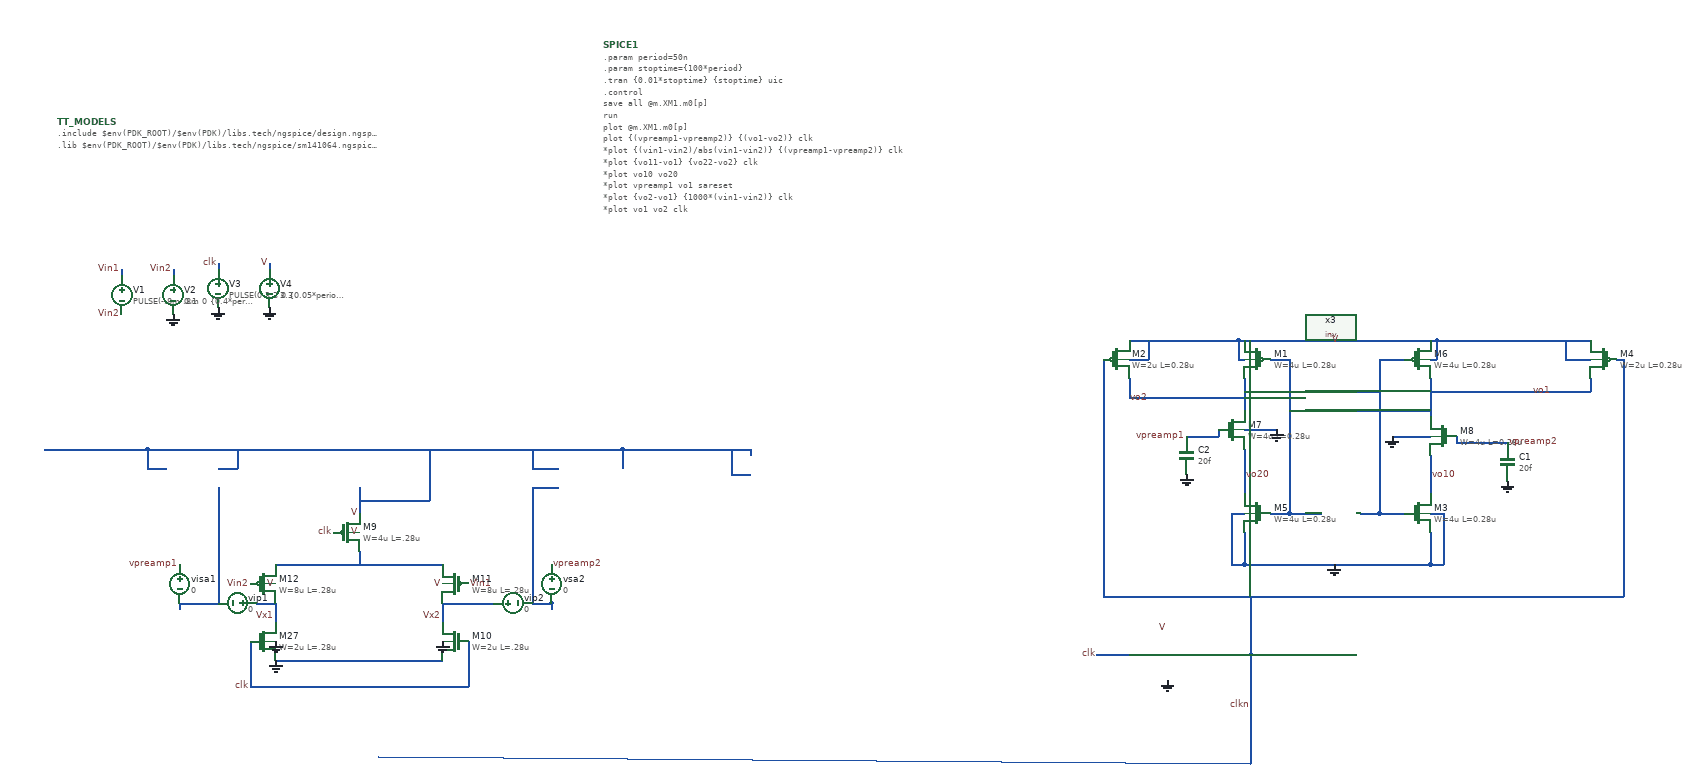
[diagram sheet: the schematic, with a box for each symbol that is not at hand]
v {xschem version=3.4.6RC file_version=1.2
}
G {}
K {}
V {}
S {}
E {}
N 260 -220 260 -210 {
lab=V}
N 180 -220 180 -210 {
lab=clk}
N 1780 200 1780 250 {
lab=GND}
N 1840 300 2340 300 {
lab=clkn}
N 2070 200 2070 250 {
lab=GND}
N 1760 170 1780 170 {
lab=GND}
N 1760 170 1760 250 {
lab=GND}
N 2070 170 2090 170 {
lab=GND}
N 2090 170 2090 250 {
lab=GND}
N 2070 130 2070 140 {
lab=vo10}
N 2070 -40 2070 20 {
lab=vo1}
N 2010 -100 2080 -100 {
lab=V}
N 1780 130 1780 140 {
lab=vo20}
N 1780 -40 1780 10 {
lab=vo2}
N 1770 -70 1780 -70 {
lab=V}
N 1770 -100 1770 -70 {
lab=V}
N 2070 -70 2080 -70 {
lab=V}
N 2080 -100 2080 -70 {
lab=V}
N 1820 -70 1850 -70 {
lab=vo1}
N 1820 170 1850 170 {
lab=vo1}
N 1850 90 1850 170 {
lab=vo1}
N 1780 40 1830 40 {
lab=GND}
N 1990 130 1990 170 {
lab=vo2}
N 1990 170 2030 170 {
lab=vo2}
N 2010 50 2070 50 {
lab=GND}
N 1990 -70 2030 -70 {
lab=vo2}
N 1760 250 1780 250 {
lab=GND}
N 1910 250 2070 250 {
lab=GND}
N 2070 250 2090 250 {
lab=GND}
N 1770 -100 1830 -100 {
lab=V}
N 1930 -100 2010 -100 {
lab=V}
N 1850 -70 1850 90 {
lab=vo1}
N 2070 80 2070 90 {
lab=vo10}
N 1780 70 1780 130 {
lab=vo20}
N 1990 -70 1990 130 {
lab=vo2}
N 2070 90 2070 130 {
lab=vo10}
N 1830 -100 1930 -100 {
lab=V}
N 1780 250 1910 250 {
lab=GND}
N 1550 390 1600 390 {
lab=clk}
N 110 -210 110 -200 {
lab=Vin2}
N 30 -210 30 -200 {
lab=Vin1}
N 700 310 700 320 {lab=#net1}
N 2080 -100 2320 -100 {lab=V}
N 1600 -100 1770 -100 {lab=V}
N 1600 -70 1630 -70 {lab=V}
N 1630 -100 1630 -70 {lab=V}
N 2280 -70 2320 -70 {lab=V}
N 2280 -100 2280 -70 {lab=V}
N 1600 -40 1600 -10 {lab=vo2}
N 1600 -10 1780 -10 {lab=vo2}
N 2070 -20 2320 -20 {lab=vo1}
N 2320 -40 2320 -20 {lab=vo1}
N 2340 300 2370 300 {lab=clkn}
N 2370 -70 2370 300 {lab=clkn}
N 2360 -70 2370 -70 {lab=clkn}
N 1560 -70 1560 250 {lab=clkn}
N 1560 250 1560 300 {lab=clkn}
N 1560 300 1840 300 {lab=clkn}
N 270 250 530 250 {lab=#net2}
N 400 230 400 250 {lab=#net2}
N 270 400 530 400 {lab=GND}
N 230 370 230 440 {lab=clk}
N 230 440 570 440 {lab=clk}
N 570 370 570 440 {lab=clk}
N 700 310 700 320 {lab=#net1}
N 120 310 120 320 {lab=#net3}
N 120 310 180 310 {lab=#net3}
N 240 310 270 310 {lab=Vx1}
N 530 310 610 310 {lab=Vx2}
N 670 310 700 310 {lab=#net1}
N 1780 -20 1990 -20 {lab=vo2}
N 1850 10 2070 10 {lab=vo1}
N 530 310 530 340 {lab=Vx2}
N 270 310 270 340 {lab=Vx1}
N 100 70 790 70 {lab=V}
N 70 100 100 100 {lab=V}
N 70 70 70 100 {lab=V}
N 70 70 100 70 {lab=V}
N 180 100 210 100 {lab=V}
N 210 70 210 100 {lab=V}
N 670 100 710 100 {lab=V}
N 670 70 670 100 {lab=V}
N 810 70 810 100 {lab=V}
N 790 70 810 70 {lab=V}
N 180 130 180 310 {lab=#net3}
N 670 130 710 130 {lab=#net1}
N 670 130 670 310 {lab=#net1}
N 1790 390 1790 560 {lab=clkn}
N 430 550 1790 560 {lab=clkn}
N 1760 390 1790 390 {lab=clkn}
N 1790 300 1790 390 {lab=clkn}
N 980 110 1010 110 {lab=V}
N 980 80 980 110 {lab=V}
N -90 70 70 70 {lab=V}
N 810 70 1010 70 {lab=V}
N 1010 70 1010 80 {lab=V}
N 980 70 980 80 {lab=V}
N 1740 40 1740 50 {lab=vpreamp1}
N 1690 50 1740 50 {lab=vpreamp1}
N 2110 60 2190 60 {lab=vpreamp2}
N 2110 50 2110 60 {lab=vpreamp2}
N 1850 170 1900 170 {lab=vo1}
N 1960 170 1990 170 {lab=vo2}
N 400 130 400 170 {lab=V}
N 400 150 510 150 {lab=V}
N 510 70 510 150 {lab=V}
C {devices/vsource.sym} 180 -180 0 0 {name=V3 value="PULSE(0 3.3 0 \{0.05*period\} \{0.05*period\} \{0.5*period\} \{1*period\})"}
C {devices/gnd.sym} 180 -150 0 0 {name=l4 lab=GND}
C {devices/lab_wire.sym} 180 -220 0 0 {name=p3 sig_type=std_logic lab=clk
}
C {devices/vsource.sym} 260 -180 0 0 {name=V4 value=3.3}
C {devices/gnd.sym} 260 -150 0 0 {name=l5 lab=GND}
C {devices/lab_wire.sym} 260 -220 0 0 {name=p7 sig_type=std_logic lab=V
}
C {devices/code_shown.sym} 780 -560 0 0 {name=SPICE1 only_toplevel=false value="

.param period=50n
.param stoptime=\{100*period\}
.tran \{0.01*stoptime\} \{stoptime\} uic 
.control
save all @m.XM1.m0[p] 
run
plot @m.XM1.m0[p]
plot \{(vpreamp1-vpreamp2)\} \{(vo1-vo2)\} clk
*plot \{(vin1-vin2)/abs(vin1-vin2)\} \{(vpreamp1-vpreamp2)\} clk
*plot \{vo11-vo1\} \{vo22-vo2\} clk
*plot vo10 vo20
*plot vpreamp1 vo1 sareset
*plot \{vo2-vo1\} \{1000*(vin1-vin2)\} clk
*plot vo1 vo2 clk
*plot \{(vin1-vin2)*10\} \{(vpreamp1-vpreamp2)\} \{clk /330\} \{vin2/(100)\}
*plot \{(vin1-vin2)*1000\} vpreamp1 vpreamp2 \{clk\} \{vin2\}
plot \{(vpreamp1-vpreamp2)\} \{(vin1-vin2)\} \{clk / 3300\}
*plot X Y clk
*plot \{(X-Y)\} \{clk/3000\}
*plot clk sareset
*plot i(vip1) i(vip2) i(visa1) i(vsa2) clk/3300
plot  \{vo1-vo2\} clk
plot \{vx1-vx2\} \{clk/30\}
plot \{vo10-vo20\} clk
.endc"}
C {devices/code.sym} -70 -440 0 0 {name=TT_MODELS 
only_toplevel=true 
format="tcleval(  @value  )"
value="
.include $env(PDK_ROOT)/$env(PDK)/libs.tech/ngspice/design.ngspice
.lib $env(PDK_ROOT)/$env(PDK)/libs.tech/ngspice/sm141064.ngspice typical
"
spice_ignore=false}
C {symbols/pfet_03v3.sym} 1800 -70 0 1 {name=M1
L=0.28u
W=4u
nf=1
m=1
ad="'int((nf+1)/2) * W/nf * 0.18u'"
pd="'2*int((nf+1)/2) * (W/nf + 0.18u)'"
as="'int((nf+2)/2) * W/nf * 0.18u'"
ps="'2*int((nf+2)/2) * (W/nf + 0.18u)'"
nrd="'0.18u / W'" nrs="'0.18u / W'"
sa=0 sb=0 sd=0
model=pfet_03v3
spiceprefix=X
}
C {symbols/pfet_03v3.sym} 1580 -70 0 0 {name=M2
L=0.28u
W=2u
nf=1
m=1
ad="'int((nf+1)/2) * W/nf * 0.18u'"
pd="'2*int((nf+1)/2) * (W/nf + 0.18u)'"
as="'int((nf+2)/2) * W/nf * 0.18u'"
ps="'2*int((nf+2)/2) * (W/nf + 0.18u)'"
nrd="'0.18u / W'" nrs="'0.18u / W'"
sa=0 sb=0 sd=0
model=pfet_03v3
spiceprefix=X
}
C {symbols/nfet_03v3.sym} 2050 170 0 0 {name=M3
L=0.28u
W=4u
nf=1
m=1
ad="'int((nf+1)/2) * W/nf * 0.18u'"
pd="'2*int((nf+1)/2) * (W/nf + 0.18u)'"
as="'int((nf+2)/2) * W/nf * 0.18u'"
ps="'2*int((nf+2)/2) * (W/nf + 0.18u)'"
nrd="'0.18u / W'" nrs="'0.18u / W'"
sa=0 sb=0 sd=0
model=nfet_03v3
spiceprefix=X
}
C {symbols/pfet_03v3.sym} 2340 -70 0 1 {name=M4
L=0.28u
W=2u
nf=1
m=1
ad="'int((nf+1)/2) * W/nf * 0.18u'"
pd="'2*int((nf+1)/2) * (W/nf + 0.18u)'"
as="'int((nf+2)/2) * W/nf * 0.18u'"
ps="'2*int((nf+2)/2) * (W/nf + 0.18u)'"
nrd="'0.18u / W'" nrs="'0.18u / W'"
sa=0 sb=0 sd=0
model=pfet_03v3
spiceprefix=X
}
C {symbols/nfet_03v3.sym} 1800 170 0 1 {name=M5
L=0.28u
W=4u
nf=1
m=1
ad="'int((nf+1)/2) * W/nf * 0.18u'"
pd="'2*int((nf+1)/2) * (W/nf + 0.18u)'"
as="'int((nf+2)/2) * W/nf * 0.18u'"
ps="'2*int((nf+2)/2) * (W/nf + 0.18u)'"
nrd="'0.18u / W'" nrs="'0.18u / W'"
sa=0 sb=0 sd=0
model=nfet_03v3
spiceprefix=X
}
C {symbols/pfet_03v3.sym} 2050 -70 0 0 {name=M6
L=0.28u
W=4u
nf=1
m=1
ad="'int((nf+1)/2) * W/nf * 0.18u'"
pd="'2*int((nf+1)/2) * (W/nf + 0.18u)'"
as="'int((nf+2)/2) * W/nf * 0.18u'"
ps="'2*int((nf+2)/2) * (W/nf + 0.18u)'"
nrd="'0.18u / W'" nrs="'0.18u / W'"
sa=0 sb=0 sd=0
model=pfet_03v3
spiceprefix=X
}
C {symbols/nfet_03v3.sym} 1760 40 0 0 {name=M7
L=0.28u
W=4u
nf=1
m=1
ad="'int((nf+1)/2) * W/nf * 0.18u'"
pd="'2*int((nf+1)/2) * (W/nf + 0.18u)'"
as="'int((nf+2)/2) * W/nf * 0.18u'"
ps="'2*int((nf+2)/2) * (W/nf + 0.18u)'"
nrd="'0.18u / W'" nrs="'0.18u / W'"
sa=0 sb=0 sd=0
model=nfet_03v3
spiceprefix=X
}
C {symbols/nfet_03v3.sym} 2090 50 0 1 {name=M8
L=0.28u
W=4u
nf=1
m=1
ad="'int((nf+1)/2) * W/nf * 0.18u'"
pd="'2*int((nf+1)/2) * (W/nf + 0.18u)'"
as="'int((nf+2)/2) * W/nf * 0.18u'"
ps="'2*int((nf+2)/2) * (W/nf + 0.18u)'"
nrd="'0.18u / W'" nrs="'0.18u / W'"
sa=0 sb=0 sd=0
model=nfet_03v3
spiceprefix=X
}
C {inv.sym} 1660 390 0 0 {name=x3 cl=0.28u wp=0.44u wn=0.22u wx=5u}
C {symbols/nfet_03v3.sym} 250 370 0 0 {name=M27
L=.28u
W=2u
nf=1
m=1
ad="'int((nf+1)/2) * W/nf * 0.18u'"
pd="'2*int((nf+1)/2) * (W/nf + 0.18u)'"
as="'int((nf+2)/2) * W/nf * 0.18u'"
ps="'2*int((nf+2)/2) * (W/nf + 0.18u)'"
nrd="'0.18u / W'" nrs="'0.18u / W'"
sa=0 sb=0 sd=0
model=nfet_03v3
spiceprefix=X
}
C {devices/lab_wire.sym} 400 170 0 0 {name=p21 lab=V
W=3u}
C {symbols/pfet_03v3.sym} 380 200 2 1 {name=M9
L=.28u
W=4u
nf=1
m=1
ad="'int((nf+1)/2) * W/nf * 0.18u'"
pd="'2*int((nf+1)/2) * (W/nf + 0.18u)'"
as="'int((nf+2)/2) * W/nf * 0.18u'"
ps="'2*int((nf+2)/2) * (W/nf + 0.18u)'"
nrd="'0.18u / W'" nrs="'0.18u / W'"
sa=0 sb=0 sd=0
model=pfet_03v3
spiceprefix=X
}
C {symbols/pfet_03v3.sym} 550 280 0 1 {name=M11
L=.28u
W=8u
nf=1
m=1
ad="'int((nf+1)/2) * W/nf * 0.18u'"
pd="'2*int((nf+1)/2) * (W/nf + 0.18u)'"
as="'int((nf+2)/2) * W/nf * 0.18u'"
ps="'2*int((nf+2)/2) * (W/nf + 0.18u)'"
nrd="'0.18u / W'" nrs="'0.18u / W'"
sa=0 sb=0 sd=0
model=pfet_03v3
spiceprefix=X
}
C {symbols/pfet_03v3.sym} 250 280 0 0 {name=M12
L=.28u
W=8u
nf=1
m=1
ad="'int((nf+1)/2) * W/nf * 0.18u'"
pd="'2*int((nf+1)/2) * (W/nf + 0.18u)'"
as="'int((nf+2)/2) * W/nf * 0.18u'"
ps="'2*int((nf+2)/2) * (W/nf + 0.18u)'"
nrd="'0.18u / W'" nrs="'0.18u / W'"
sa=0 sb=0 sd=0
model=pfet_03v3
spiceprefix=X
}
C {devices/lab_wire.sym} 1930 -100 0 0 {name=p4 lab=V
W=3u}
C {devices/gnd.sym} 1660 430 0 0 {name=l1 lab=GND}
C {devices/gnd.sym} 270 400 0 0 {name=l2 lab=GND}
C {devices/lab_wire.sym} 230 280 0 0 {name=p5 sig_type=std_logic lab=Vin2}
C {devices/lab_wire.sym} 570 280 0 1 {name=p6 sig_type=std_logic lab=Vin1}
C {devices/lab_wire.sym} 230 440 0 0 {name=p8 sig_type=std_logic lab=clk
}
C {devices/lab_wire.sym} 1550 390 0 0 {name=p9 sig_type=std_logic lab=clk
}
C {devices/lab_wire.sym} 120 250 0 0 {name=p10 sig_type=std_logic lab=vpreamp1}
C {devices/lab_wire.sym} 1690 50 0 0 {name=p12 sig_type=std_logic lab=vpreamp1}
C {devices/lab_wire.sym} 2190 60 0 1 {name=p14 sig_type=std_logic lab=vpreamp2
}
C {devices/lab_wire.sym} 1660 350 0 0 {name=p16 lab=V
W=3u}
C {devices/lab_wire.sym} 2260 -20 0 0 {name=p15 sig_type=std_logic lab=vo1
}
C {devices/lab_wire.sym} 1600 -10 0 1 {name=p17 sig_type=std_logic lab=vo2}
C {devices/vsource.sym} 30 -170 0 0 {name=V1 value="PULSE(-.8m .8m 0 \{0.4*period\} \{0.4*period\} \{8*period\} \{16*period\})"}
C {devices/vsource.sym} 110 -170 0 0 {name=V2 value=0.1}
C {devices/gnd.sym} 110 -140 0 0 {name=l3 lab=GND}
C {devices/lab_wire.sym} 30 -210 0 0 {name=p1 sig_type=std_logic lab=Vin1}
C {devices/lab_wire.sym} 110 -210 0 0 {name=p2 sig_type=std_logic lab=Vin2}
C {devices/lab_wire.sym} 30 -140 0 0 {name=p13 sig_type=std_logic lab=Vin2}
C {devices/vsource.sym} 210 310 1 0 {name=vip1 value=0}
C {devices/vsource.sym} 120 280 0 0 {name=visa1 value=0}
C {devices/vsource.sym} 640 310 3 0 {name=vip2 value=0}
C {devices/vsource.sym} 700 280 0 0 {name=vsa2 value=0}
C {devices/lab_wire.sym} 700 250 0 1 {name=p23 sig_type=std_logic lab=vpreamp2
}
C {devices/gnd.sym} 1920 250 0 0 {name=l6 lab=GND}
C {symbols/nfet_03v3.sym} 550 370 0 1 {name=M10
L=.28u
W=2u
nf=1
m=1
ad="'int((nf+1)/2) * W/nf * 0.18u'"
pd="'2*int((nf+1)/2) * (W/nf + 0.18u)'"
as="'int((nf+2)/2) * W/nf * 0.18u'"
ps="'2*int((nf+2)/2) * (W/nf + 0.18u)'"
nrd="'0.18u / W'" nrs="'0.18u / W'"
sa=0 sb=0 sd=0
model=nfet_03v3
spiceprefix=X
}
C {devices/lab_wire.sym} 360 200 0 0 {name=p11 sig_type=std_logic lab=clk
}
C {devices/gnd.sym} 2010 50 0 0 {name=l9 lab=GND}
C {devices/gnd.sym} 1830 40 0 0 {name=l10 lab=GND}
C {devices/lab_wire.sym} 1780 110 0 1 {name=p19 sig_type=std_logic lab=vo20}
C {devices/lab_wire.sym} 2070 110 0 1 {name=p20 sig_type=std_logic lab=vo10}
C {devices/lab_wire.sym} 1790 470 0 0 {name=p18 sig_type=std_logic lab=clkn
}
C {devices/lab_wire.sym} 530 330 0 0 {name=p27 sig_type=std_logic lab=Vx2
}
C {devices/lab_wire.sym} 270 330 0 0 {name=p28 sig_type=std_logic lab=Vx1
}
C {devices/capa.sym} 2190 90 0 0 {name=C1
m=1
value=20f
footprint=1206
device="ceramic capacitor"}
C {devices/capa.sym} 1690 80 0 0 {name=C2
m=1
value=20f
footprint=1206
device="ceramic capacitor"}
C {devices/gnd.sym} 1690 110 0 0 {name=l14 lab=GND}
C {devices/gnd.sym} 2190 120 0 0 {name=l15 lab=GND}
C {devices/lab_wire.sym} 400 200 0 0 {name=p22 lab=V}
C {devices/lab_wire.sym} 530 280 0 0 {name=p24 lab=V
W=3u}
C {devices/lab_wire.sym} 270 280 0 0 {name=p26 lab=V
W=3u}
C {devices/gnd.sym} 270 370 0 0 {name=l7 lab=GND}
C {devices/gnd.sym} 530 370 0 0 {name=l8 lab=GND}
